VERSION 5.7 ;
  NOWIREEXTENSIONATPIN ON ;
  DIVIDERCHAR "/" ;
  BUSBITCHARS "[]" ;
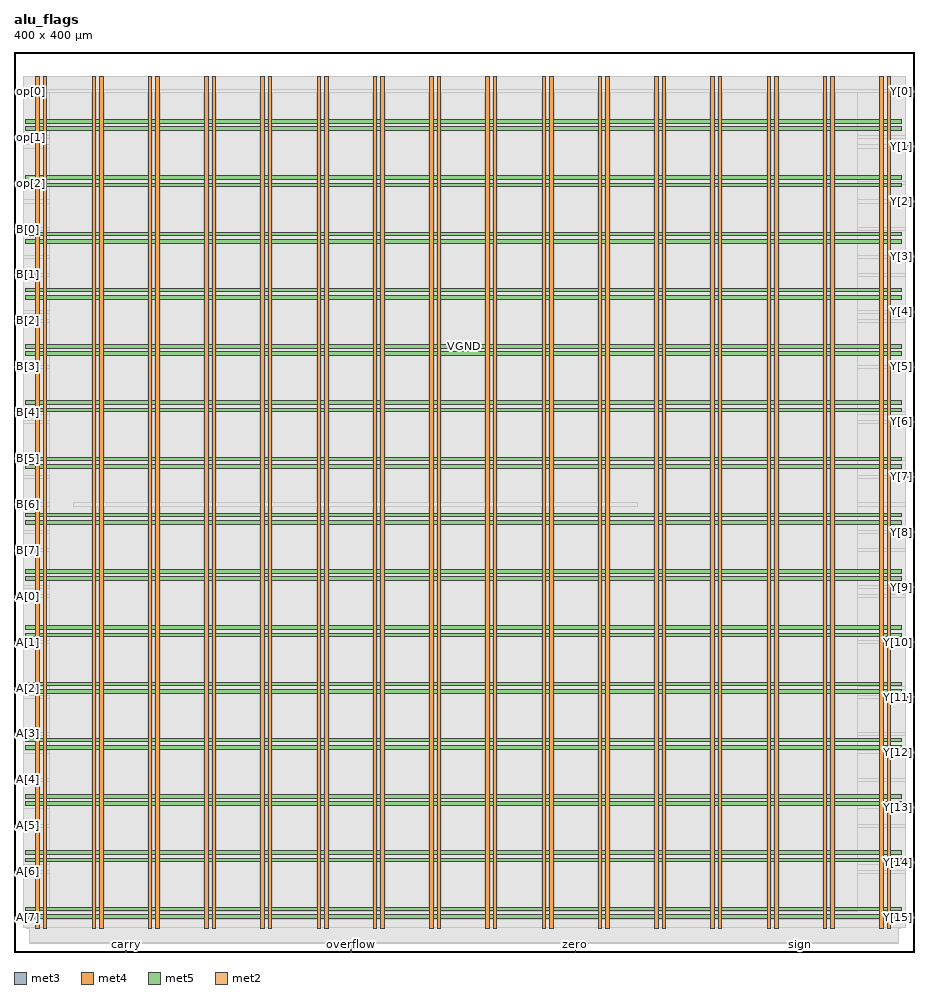
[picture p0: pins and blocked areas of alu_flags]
MACRO alu_flags
  CLASS BLOCK ;
  FOREIGN alu_flags ;
  ORIGIN 0.000 0.000 ;
  SIZE 400.000 BY 400.000 ;
  PIN A[0]
    DIRECTION INPUT ;
    USE SIGNAL ;
    ANTENNAGATEAREA 1.971000 ;
    PORT
      LAYER met3 ;
        RECT 0.000 157.800 4.000 158.400 ;
    END
  END A[0]
  PIN A[1]
    DIRECTION INPUT ;
    USE SIGNAL ;
    ANTENNAGATEAREA 1.004700 ;
    ANTENNADIFFAREA 0.434700 ;
    PORT
      LAYER met3 ;
        RECT 0.000 137.400 4.000 138.000 ;
    END
  END A[1]
  PIN A[2]
    DIRECTION INPUT ;
    USE SIGNAL ;
    ANTENNAGATEAREA 1.065000 ;
    PORT
      LAYER met3 ;
        RECT 0.000 117.000 4.000 117.600 ;
    END
  END A[2]
  PIN A[3]
    DIRECTION INPUT ;
    USE SIGNAL ;
    ANTENNAGATEAREA 0.696000 ;
    PORT
      LAYER met3 ;
        RECT 0.000 96.600 4.000 97.200 ;
    END
  END A[3]
  PIN A[4]
    DIRECTION INPUT ;
    USE SIGNAL ;
    ANTENNAGATEAREA 1.564500 ;
    PORT
      LAYER met3 ;
        RECT 0.000 76.200 4.000 76.800 ;
    END
  END A[4]
  PIN A[5]
    DIRECTION INPUT ;
    USE SIGNAL ;
    ANTENNAGATEAREA 1.933500 ;
    PORT
      LAYER met3 ;
        RECT 0.000 55.800 4.000 56.400 ;
    END
  END A[5]
  PIN A[6]
    DIRECTION INPUT ;
    USE SIGNAL ;
    ANTENNAGATEAREA 1.812000 ;
    PORT
      LAYER met3 ;
        RECT 0.000 35.400 4.000 36.000 ;
    END
  END A[6]
  PIN A[7]
    DIRECTION INPUT ;
    USE SIGNAL ;
    ANTENNAGATEAREA 1.807500 ;
    PORT
      LAYER met3 ;
        RECT 0.000 15.000 4.000 15.600 ;
    END
  END A[7]
  PIN B[0]
    DIRECTION INPUT ;
    USE SIGNAL ;
    ANTENNAGATEAREA 2.554500 ;
    PORT
      LAYER met3 ;
        RECT 0.000 321.000 4.000 321.600 ;
    END
  END B[0]
  PIN B[1]
    DIRECTION INPUT ;
    USE SIGNAL ;
    ANTENNAGATEAREA 2.802000 ;
    PORT
      LAYER met3 ;
        RECT 0.000 300.600 4.000 301.200 ;
    END
  END B[1]
  PIN B[2]
    DIRECTION INPUT ;
    USE SIGNAL ;
    ANTENNAGATEAREA 2.218500 ;
    PORT
      LAYER met3 ;
        RECT 0.000 280.200 4.000 280.800 ;
    END
  END B[2]
  PIN B[3]
    DIRECTION INPUT ;
    USE SIGNAL ;
    ANTENNAGATEAREA 1.195500 ;
    PORT
      LAYER met3 ;
        RECT 0.000 259.800 4.000 260.400 ;
    END
  END B[3]
  PIN B[4]
    DIRECTION INPUT ;
    USE SIGNAL ;
    ANTENNAGATEAREA 0.943500 ;
    PORT
      LAYER met3 ;
        RECT 0.000 239.400 4.000 240.000 ;
    END
  END B[4]
  PIN B[5]
    DIRECTION INPUT ;
    USE SIGNAL ;
    ANTENNAGATEAREA 2.097000 ;
    PORT
      LAYER met3 ;
        RECT 0.000 219.000 4.000 219.600 ;
    END
  END B[5]
  PIN B[6]
    DIRECTION INPUT ;
    USE SIGNAL ;
    ANTENNAGATEAREA 1.564500 ;
    PORT
      LAYER met3 ;
        RECT 0.000 198.600 4.000 199.200 ;
    END
  END B[6]
  PIN B[7]
    DIRECTION INPUT ;
    USE SIGNAL ;
    ANTENNAGATEAREA 2.428500 ;
    PORT
      LAYER met3 ;
        RECT 0.000 178.200 4.000 178.800 ;
    END
  END B[7]
  PIN VGND
    DIRECTION INOUT ;
    USE GROUND ;
    PORT
      LAYER met4 ;
        RECT 13.020 10.640 14.620 389.200 ;
    END
    PORT
      LAYER met4 ;
        RECT 38.020 10.640 39.620 389.200 ;
    END
    PORT
      LAYER met4 ;
        RECT 63.020 10.640 64.620 389.200 ;
    END
    PORT
      LAYER met4 ;
        RECT 88.020 10.640 89.620 389.200 ;
    END
    PORT
      LAYER met4 ;
        RECT 113.020 10.640 114.620 389.200 ;
    END
    PORT
      LAYER met4 ;
        RECT 138.020 10.640 139.620 389.200 ;
    END
    PORT
      LAYER met4 ;
        RECT 163.020 10.640 164.620 389.200 ;
    END
    PORT
      LAYER met4 ;
        RECT 188.020 10.640 189.620 389.200 ;
    END
    PORT
      LAYER met4 ;
        RECT 213.020 10.640 214.620 389.200 ;
    END
    PORT
      LAYER met4 ;
        RECT 238.020 10.640 239.620 389.200 ;
    END
    PORT
      LAYER met4 ;
        RECT 263.020 10.640 264.620 389.200 ;
    END
    PORT
      LAYER met4 ;
        RECT 288.020 10.640 289.620 389.200 ;
    END
    PORT
      LAYER met4 ;
        RECT 313.020 10.640 314.620 389.200 ;
    END
    PORT
      LAYER met4 ;
        RECT 338.020 10.640 339.620 389.200 ;
    END
    PORT
      LAYER met4 ;
        RECT 363.020 10.640 364.620 389.200 ;
    END
    PORT
      LAYER met4 ;
        RECT 388.020 10.640 389.620 389.200 ;
    END
    PORT
      LAYER met5 ;
        RECT 5.280 18.380 394.460 19.980 ;
    END
    PORT
      LAYER met5 ;
        RECT 5.280 43.380 394.460 44.980 ;
    END
    PORT
      LAYER met5 ;
        RECT 5.280 68.380 394.460 69.980 ;
    END
    PORT
      LAYER met5 ;
        RECT 5.280 93.380 394.460 94.980 ;
    END
    PORT
      LAYER met5 ;
        RECT 5.280 118.380 394.460 119.980 ;
    END
    PORT
      LAYER met5 ;
        RECT 5.280 143.380 394.460 144.980 ;
    END
    PORT
      LAYER met5 ;
        RECT 5.280 168.380 394.460 169.980 ;
    END
    PORT
      LAYER met5 ;
        RECT 5.280 193.380 394.460 194.980 ;
    END
    PORT
      LAYER met5 ;
        RECT 5.280 218.380 394.460 219.980 ;
    END
    PORT
      LAYER met5 ;
        RECT 5.280 243.380 394.460 244.980 ;
    END
    PORT
      LAYER met5 ;
        RECT 5.280 268.380 394.460 269.980 ;
    END
    PORT
      LAYER met5 ;
        RECT 5.280 293.380 394.460 294.980 ;
    END
    PORT
      LAYER met5 ;
        RECT 5.280 318.380 394.460 319.980 ;
    END
    PORT
      LAYER met5 ;
        RECT 5.280 343.380 394.460 344.980 ;
    END
    PORT
      LAYER met5 ;
        RECT 5.280 368.380 394.460 369.980 ;
    END
  END VGND
  PIN VPWR
    DIRECTION INOUT ;
    USE POWER ;
    PORT
      LAYER met4 ;
        RECT 9.720 10.640 11.320 389.200 ;
    END
    PORT
      LAYER met4 ;
        RECT 34.720 10.640 36.320 389.200 ;
    END
    PORT
      LAYER met4 ;
        RECT 59.720 10.640 61.320 389.200 ;
    END
    PORT
      LAYER met4 ;
        RECT 84.720 10.640 86.320 389.200 ;
    END
    PORT
      LAYER met4 ;
        RECT 109.720 10.640 111.320 389.200 ;
    END
    PORT
      LAYER met4 ;
        RECT 134.720 10.640 136.320 389.200 ;
    END
    PORT
      LAYER met4 ;
        RECT 159.720 10.640 161.320 389.200 ;
    END
    PORT
      LAYER met4 ;
        RECT 184.720 10.640 186.320 389.200 ;
    END
    PORT
      LAYER met4 ;
        RECT 209.720 10.640 211.320 389.200 ;
    END
    PORT
      LAYER met4 ;
        RECT 234.720 10.640 236.320 389.200 ;
    END
    PORT
      LAYER met4 ;
        RECT 259.720 10.640 261.320 389.200 ;
    END
    PORT
      LAYER met4 ;
        RECT 284.720 10.640 286.320 389.200 ;
    END
    PORT
      LAYER met4 ;
        RECT 309.720 10.640 311.320 389.200 ;
    END
    PORT
      LAYER met4 ;
        RECT 334.720 10.640 336.320 389.200 ;
    END
    PORT
      LAYER met4 ;
        RECT 359.720 10.640 361.320 389.200 ;
    END
    PORT
      LAYER met4 ;
        RECT 384.720 10.640 386.320 389.200 ;
    END
    PORT
      LAYER met5 ;
        RECT 5.280 15.080 394.460 16.680 ;
    END
    PORT
      LAYER met5 ;
        RECT 5.280 40.080 394.460 41.680 ;
    END
    PORT
      LAYER met5 ;
        RECT 5.280 65.080 394.460 66.680 ;
    END
    PORT
      LAYER met5 ;
        RECT 5.280 90.080 394.460 91.680 ;
    END
    PORT
      LAYER met5 ;
        RECT 5.280 115.080 394.460 116.680 ;
    END
    PORT
      LAYER met5 ;
        RECT 5.280 140.080 394.460 141.680 ;
    END
    PORT
      LAYER met5 ;
        RECT 5.280 165.080 394.460 166.680 ;
    END
    PORT
      LAYER met5 ;
        RECT 5.280 190.080 394.460 191.680 ;
    END
    PORT
      LAYER met5 ;
        RECT 5.280 215.080 394.460 216.680 ;
    END
    PORT
      LAYER met5 ;
        RECT 5.280 240.080 394.460 241.680 ;
    END
    PORT
      LAYER met5 ;
        RECT 5.280 265.080 394.460 266.680 ;
    END
    PORT
      LAYER met5 ;
        RECT 5.280 290.080 394.460 291.680 ;
    END
    PORT
      LAYER met5 ;
        RECT 5.280 315.080 394.460 316.680 ;
    END
    PORT
      LAYER met5 ;
        RECT 5.280 340.080 394.460 341.680 ;
    END
    PORT
      LAYER met5 ;
        RECT 5.280 365.080 394.460 366.680 ;
    END
  END VPWR
  PIN Y[0]
    DIRECTION OUTPUT TRISTATE ;
    USE SIGNAL ;
    ANTENNADIFFAREA 0.715500 ;
    PORT
      LAYER met3 ;
        RECT 396.000 382.200 400.000 382.800 ;
    END
  END Y[0]
  PIN Y[10]
    DIRECTION OUTPUT TRISTATE ;
    USE SIGNAL ;
    ANTENNAGATEAREA 0.126000 ;
    ANTENNADIFFAREA 0.621000 ;
    PORT
      LAYER met3 ;
        RECT 396.000 137.400 400.000 138.000 ;
    END
  END Y[10]
  PIN Y[11]
    DIRECTION OUTPUT TRISTATE ;
    USE SIGNAL ;
    ANTENNAGATEAREA 0.126000 ;
    ANTENNADIFFAREA 0.621000 ;
    PORT
      LAYER met3 ;
        RECT 396.000 112.920 400.000 113.520 ;
    END
  END Y[11]
  PIN Y[12]
    DIRECTION OUTPUT TRISTATE ;
    USE SIGNAL ;
    ANTENNAGATEAREA 0.126000 ;
    ANTENNADIFFAREA 0.621000 ;
    PORT
      LAYER met3 ;
        RECT 396.000 88.440 400.000 89.040 ;
    END
  END Y[12]
  PIN Y[13]
    DIRECTION OUTPUT TRISTATE ;
    USE SIGNAL ;
    ANTENNAGATEAREA 0.560700 ;
    ANTENNADIFFAREA 1.055700 ;
    PORT
      LAYER met3 ;
        RECT 396.000 63.960 400.000 64.560 ;
    END
  END Y[13]
  PIN Y[14]
    DIRECTION OUTPUT TRISTATE ;
    USE SIGNAL ;
    ANTENNAGATEAREA 0.126000 ;
    ANTENNADIFFAREA 0.621000 ;
    PORT
      LAYER met3 ;
        RECT 396.000 39.480 400.000 40.080 ;
    END
  END Y[14]
  PIN Y[15]
    DIRECTION OUTPUT TRISTATE ;
    USE SIGNAL ;
    ANTENNAGATEAREA 0.126000 ;
    ANTENNADIFFAREA 0.621000 ;
    PORT
      LAYER met3 ;
        RECT 396.000 15.000 400.000 15.600 ;
    END
  END Y[15]
  PIN Y[1]
    DIRECTION OUTPUT TRISTATE ;
    USE SIGNAL ;
    ANTENNAGATEAREA 2.734200 ;
    ANTENNADIFFAREA 3.053700 ;
    PORT
      LAYER met3 ;
        RECT 396.000 357.720 400.000 358.320 ;
    END
  END Y[1]
  PIN Y[2]
    DIRECTION OUTPUT TRISTATE ;
    USE SIGNAL ;
    ANTENNAGATEAREA 1.864800 ;
    ANTENNADIFFAREA 2.480800 ;
    PORT
      LAYER met3 ;
        RECT 396.000 333.240 400.000 333.840 ;
    END
  END Y[2]
  PIN Y[3]
    DIRECTION OUTPUT TRISTATE ;
    USE SIGNAL ;
    ANTENNAGATEAREA 1.430100 ;
    ANTENNADIFFAREA 2.367600 ;
    PORT
      LAYER met3 ;
        RECT 396.000 308.760 400.000 309.360 ;
    END
  END Y[3]
  PIN Y[4]
    DIRECTION OUTPUT TRISTATE ;
    USE SIGNAL ;
    ANTENNAGATEAREA 0.126000 ;
    ANTENNADIFFAREA 0.340600 ;
    PORT
      LAYER met3 ;
        RECT 396.000 284.280 400.000 284.880 ;
    END
  END Y[4]
  PIN Y[5]
    DIRECTION OUTPUT TRISTATE ;
    USE SIGNAL ;
    ANTENNAGATEAREA 0.126000 ;
    ANTENNADIFFAREA 0.715500 ;
    PORT
      LAYER met3 ;
        RECT 396.000 259.800 400.000 260.400 ;
    END
  END Y[5]
  PIN Y[6]
    DIRECTION OUTPUT TRISTATE ;
    USE SIGNAL ;
    ANTENNAGATEAREA 0.126000 ;
    ANTENNADIFFAREA 0.742000 ;
    PORT
      LAYER met3 ;
        RECT 396.000 235.320 400.000 235.920 ;
    END
  END Y[6]
  PIN Y[7]
    DIRECTION OUTPUT TRISTATE ;
    USE SIGNAL ;
    ANTENNAGATEAREA 0.285000 ;
    ANTENNADIFFAREA 0.452000 ;
    PORT
      LAYER met3 ;
        RECT 396.000 210.840 400.000 211.440 ;
    END
  END Y[7]
  PIN Y[8]
    DIRECTION OUTPUT TRISTATE ;
    USE SIGNAL ;
    ANTENNAGATEAREA 0.126000 ;
    ANTENNADIFFAREA 0.621000 ;
    PORT
      LAYER met3 ;
        RECT 396.000 186.360 400.000 186.960 ;
    END
  END Y[8]
  PIN Y[9]
    DIRECTION OUTPUT TRISTATE ;
    USE SIGNAL ;
    ANTENNAGATEAREA 0.126000 ;
    ANTENNADIFFAREA 0.621000 ;
    PORT
      LAYER met3 ;
        RECT 396.000 161.880 400.000 162.480 ;
    END
  END Y[9]
  PIN carry
    DIRECTION OUTPUT TRISTATE ;
    USE SIGNAL ;
    ANTENNADIFFAREA 0.445500 ;
    PORT
      LAYER met2 ;
        RECT 49.770 0.000 50.050 4.000 ;
    END
  END carry
  PIN op[0]
    DIRECTION INPUT ;
    USE SIGNAL ;
    ANTENNAGATEAREA 1.750500 ;
    PORT
      LAYER met3 ;
        RECT 0.000 382.200 4.000 382.800 ;
    END
  END op[0]
  PIN op[1]
    DIRECTION INPUT ;
    USE SIGNAL ;
    ANTENNAGATEAREA 1.989000 ;
    PORT
      LAYER met3 ;
        RECT 0.000 361.800 4.000 362.400 ;
    END
  END op[1]
  PIN op[2]
    DIRECTION INPUT ;
    USE SIGNAL ;
    ANTENNAGATEAREA 2.362500 ;
    PORT
      LAYER met3 ;
        RECT 0.000 341.400 4.000 342.000 ;
    END
  END op[2]
  PIN overflow
    DIRECTION OUTPUT TRISTATE ;
    USE SIGNAL ;
    ANTENNADIFFAREA 0.445500 ;
    PORT
      LAYER met2 ;
        RECT 149.590 0.000 149.870 4.000 ;
    END
  END overflow
  PIN sign
    DIRECTION OUTPUT TRISTATE ;
    USE SIGNAL ;
    ANTENNADIFFAREA 0.445500 ;
    PORT
      LAYER met2 ;
        RECT 349.230 0.000 349.510 4.000 ;
    END
  END sign
  PIN zero
    DIRECTION OUTPUT TRISTATE ;
    USE SIGNAL ;
    ANTENNADIFFAREA 0.340600 ;
    PORT
      LAYER met2 ;
        RECT 249.410 0.000 249.690 4.000 ;
    END
  END zero
  OBS
      LAYER li1 ;
        RECT 5.520 10.795 394.220 389.045 ;
      LAYER met1 ;
        RECT 5.520 10.640 394.220 389.200 ;
      LAYER met2 ;
        RECT 7.000 4.280 393.200 389.145 ;
        RECT 7.000 3.670 49.490 4.280 ;
        RECT 50.330 3.670 149.310 4.280 ;
        RECT 150.150 3.670 249.130 4.280 ;
        RECT 249.970 3.670 348.950 4.280 ;
        RECT 349.790 3.670 393.200 4.280 ;
      LAYER met3 ;
        RECT 4.000 383.200 396.000 389.125 ;
        RECT 4.400 381.800 395.600 383.200 ;
        RECT 4.000 362.800 396.000 381.800 ;
        RECT 4.400 361.400 396.000 362.800 ;
        RECT 4.000 358.720 396.000 361.400 ;
        RECT 4.000 357.320 395.600 358.720 ;
        RECT 4.000 342.400 396.000 357.320 ;
        RECT 4.400 341.000 396.000 342.400 ;
        RECT 4.000 334.240 396.000 341.000 ;
        RECT 4.000 332.840 395.600 334.240 ;
        RECT 4.000 322.000 396.000 332.840 ;
        RECT 4.400 320.600 396.000 322.000 ;
        RECT 4.000 309.760 396.000 320.600 ;
        RECT 4.000 308.360 395.600 309.760 ;
        RECT 4.000 301.600 396.000 308.360 ;
        RECT 4.400 300.200 396.000 301.600 ;
        RECT 4.000 285.280 396.000 300.200 ;
        RECT 4.000 283.880 395.600 285.280 ;
        RECT 4.000 281.200 396.000 283.880 ;
        RECT 4.400 279.800 396.000 281.200 ;
        RECT 4.000 260.800 396.000 279.800 ;
        RECT 4.400 259.400 395.600 260.800 ;
        RECT 4.000 240.400 396.000 259.400 ;
        RECT 4.400 239.000 396.000 240.400 ;
        RECT 4.000 236.320 396.000 239.000 ;
        RECT 4.000 234.920 395.600 236.320 ;
        RECT 4.000 220.000 396.000 234.920 ;
        RECT 4.400 218.600 396.000 220.000 ;
        RECT 4.000 211.840 396.000 218.600 ;
        RECT 4.000 210.440 395.600 211.840 ;
        RECT 4.000 199.600 396.000 210.440 ;
        RECT 4.400 198.200 396.000 199.600 ;
        RECT 4.000 187.360 396.000 198.200 ;
        RECT 4.000 185.960 395.600 187.360 ;
        RECT 4.000 179.200 396.000 185.960 ;
        RECT 4.400 177.800 396.000 179.200 ;
        RECT 4.000 162.880 396.000 177.800 ;
        RECT 4.000 161.480 395.600 162.880 ;
        RECT 4.000 158.800 396.000 161.480 ;
        RECT 4.400 157.400 396.000 158.800 ;
        RECT 4.000 138.400 396.000 157.400 ;
        RECT 4.400 137.000 395.600 138.400 ;
        RECT 4.000 118.000 396.000 137.000 ;
        RECT 4.400 116.600 396.000 118.000 ;
        RECT 4.000 113.920 396.000 116.600 ;
        RECT 4.000 112.520 395.600 113.920 ;
        RECT 4.000 97.600 396.000 112.520 ;
        RECT 4.400 96.200 396.000 97.600 ;
        RECT 4.000 89.440 396.000 96.200 ;
        RECT 4.000 88.040 395.600 89.440 ;
        RECT 4.000 77.200 396.000 88.040 ;
        RECT 4.400 75.800 396.000 77.200 ;
        RECT 4.000 64.960 396.000 75.800 ;
        RECT 4.000 63.560 395.600 64.960 ;
        RECT 4.000 56.800 396.000 63.560 ;
        RECT 4.400 55.400 396.000 56.800 ;
        RECT 4.000 40.480 396.000 55.400 ;
        RECT 4.000 39.080 395.600 40.480 ;
        RECT 4.000 36.400 396.000 39.080 ;
        RECT 4.400 35.000 396.000 36.400 ;
        RECT 4.000 16.000 396.000 35.000 ;
        RECT 4.400 14.600 395.600 16.000 ;
        RECT 4.000 10.715 396.000 14.600 ;
      LAYER met4 ;
        RECT 15.935 17.855 34.320 381.985 ;
        RECT 36.720 17.855 37.620 381.985 ;
        RECT 40.020 17.855 59.320 381.985 ;
        RECT 61.720 17.855 62.620 381.985 ;
        RECT 65.020 17.855 84.320 381.985 ;
        RECT 86.720 17.855 87.620 381.985 ;
        RECT 90.020 17.855 109.320 381.985 ;
        RECT 111.720 17.855 112.620 381.985 ;
        RECT 115.020 17.855 134.320 381.985 ;
        RECT 136.720 17.855 137.620 381.985 ;
        RECT 140.020 17.855 159.320 381.985 ;
        RECT 161.720 17.855 162.620 381.985 ;
        RECT 165.020 17.855 184.320 381.985 ;
        RECT 186.720 17.855 187.620 381.985 ;
        RECT 190.020 17.855 209.320 381.985 ;
        RECT 211.720 17.855 212.620 381.985 ;
        RECT 215.020 17.855 234.320 381.985 ;
        RECT 236.720 17.855 237.620 381.985 ;
        RECT 240.020 17.855 259.320 381.985 ;
        RECT 261.720 17.855 262.620 381.985 ;
        RECT 265.020 17.855 284.320 381.985 ;
        RECT 286.720 17.855 287.620 381.985 ;
        RECT 290.020 17.855 309.320 381.985 ;
        RECT 311.720 17.855 312.620 381.985 ;
        RECT 315.020 17.855 334.320 381.985 ;
        RECT 336.720 17.855 337.620 381.985 ;
        RECT 340.020 17.855 359.320 381.985 ;
        RECT 361.720 17.855 362.620 381.985 ;
        RECT 365.020 17.855 375.065 381.985 ;
      LAYER met5 ;
        RECT 26.340 198.100 277.260 199.700 ;
  END
END alu_flags
END LIBRARY

